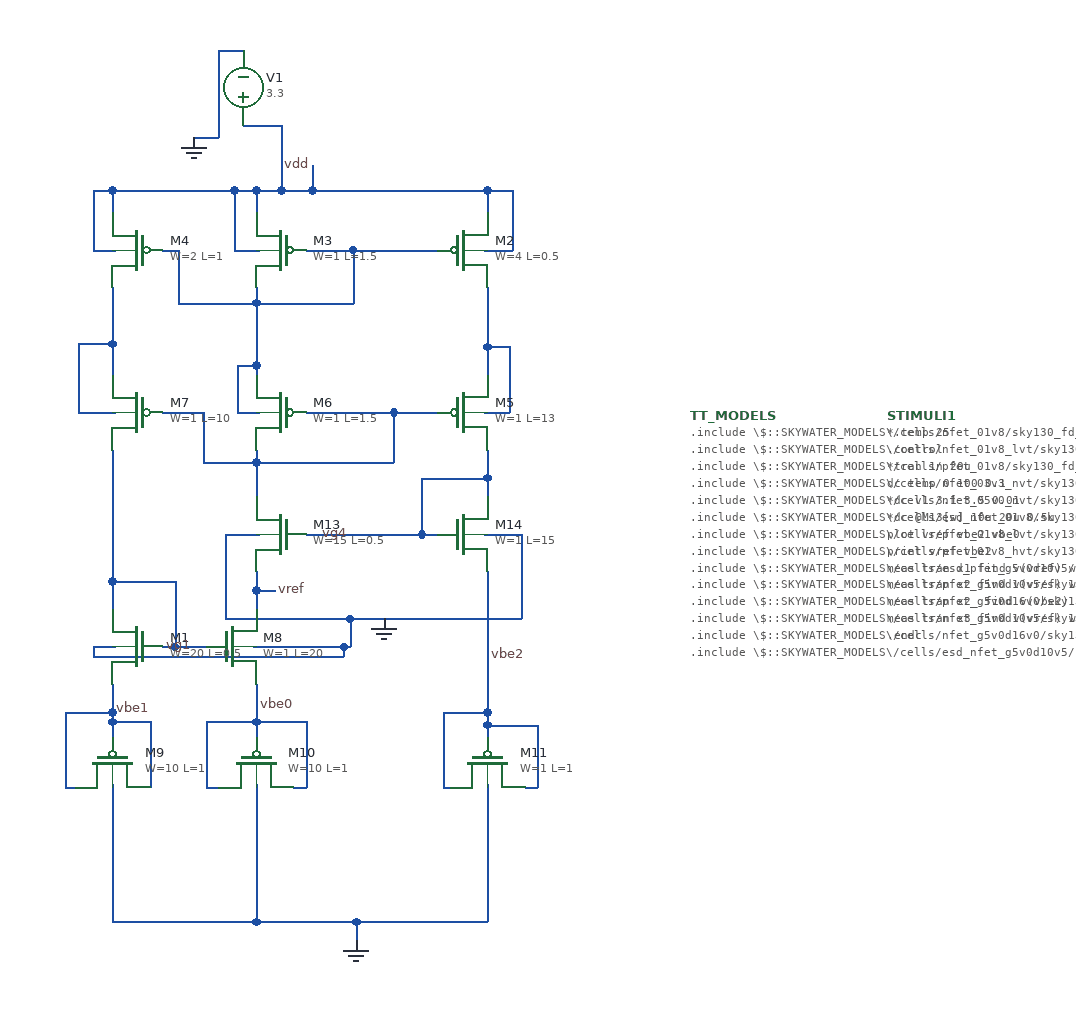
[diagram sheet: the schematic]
v {xschem version=2.9.9 file_version=1.2 }
G {}
K {}
V {}
S {}
E {}
N -125 -927.5 -125 -910 { lab=vdd}
N -27.5 -927.5 -10 -927.5 { lab=vdd}
N -10 -927.5 -10 -910 { lab=vdd}
N 175 -927.5 175 -910 { lab=vdd}
N 35 -927.5 175 -927.5 { lab=vdd}
N -27.5 -880 -7.5 -880 { lab=vdd}
N -27.5 -927.5 -27.5 -880 { lab=vdd}
N -140 -880 -122.5 -880 { lab=vdd}
N -140 -927.5 -140 -880 { lab=vdd}
N -140 -927.5 -125 -927.5 { lab=vdd}
N -125 -805 -125 -780 { lab=#net1}
N -152.5 -750 -122.5 -750 { lab=#net1}
N -152.5 -805 -152.5 -750 { lab=#net1}
N -152.5 -805 -125 -805 { lab=#net1}
N -125 -615 -125 -592.5 { lab=vg1}
N -85 -750 -52.5 -750 { lab=#net2}
N -52.5 -750 -52.5 -710 { lab=#net2}
N 100 -750 100 -710 { lab=#net2}
N 30 -750 100 -750 { lab=#net2}
N 100 -750 135 -750 { lab=#net2}
N -25 -750 -7.5 -750 { lab=#net3}
N -25 -787.5 -25 -750 { lab=#net3}
N -25 -787.5 -10 -787.5 { lab=#net3}
N -10 -787.5 -10 -780 { lab=#net3}
N -10 -837.5 -10 -787.5 { lab=#net3}
N -85 -880 -72.5 -880 { lab=#net3}
N -72.5 -880 -72.5 -837.5 { lab=#net3}
N 67.5 -880 67.5 -837.5 { lab=#net3}
N 30 -880 67.5 -880 { lab=#net3}
N 67.5 -880 135 -880 { lab=#net3}
N 172.5 -880 195 -880 { lab=vdd}
N 195 -927.5 195 -880 { lab=vdd}
N 175 -927.5 195 -927.5 { lab=vdd}
N 175 -802.5 175 -780 { lab=#net4}
N 172.5 -750 192.5 -750 { lab=#net4}
N 192.5 -802.5 192.5 -750 { lab=#net4}
N 175 -802.5 192.5 -802.5 { lab=#net4}
N 175 -697.5 175 -682.5 { lab=vg4}
N -10 -710 -10 -682.5 { lab=#net2}
N 122.5 -652.5 135 -652.5 { lab=vg4}
N 122.5 -697.5 175 -697.5 { lab=vg4}
N 122.5 -697.5 122.5 -652.5 { lab=vg4}
N -10 -607.5 -10 -592.5 { lab=vref}
N -75 -562.5 -50 -562.5 { lab=vg1}
N -95 -502.5 -95 -450 { lab=vbe1}
N -162.5 -450 -155 -450 { lab=vbe1}
N -50 -450 -40 -450 { lab=vbe0}
N -50 -502.5 -50 -450 { lab=vbe0}
N 20 -450 30 -450 { lab=vbe0}
N 30 -502.5 30 -450 { lab=vbe0}
N 140 -450 145 -450 { lab=vbe2}
N 205 -450 215 -450 { lab=vbe2}
N 215 -500 215 -450 { lab=vbe2}
N -125 -615 -75 -615 { lab=vg1}
N -75 -615 -75 -562.5 { lab=vg1}
N 175 -452.5 175 -342.5 { lab=GND}
N -125 -452.5 -125 -342.5 { lab=GND}
N -10 -452.5 -10 -342.5 { lab=GND}
N -60 -970 -40 -970 { lab=GND}
N 35 -947.5 35 -927.5 { lab=vdd}
N 70 -342.5 70 -327.5 { lab=GND}
N -10 -607.5 5 -607.5 { lab=vref}
N -35 -652.5 -7.5 -652.5 { lab=GND}
N -35 -652.5 -35 -585 { lab=GND}
N 65 -585 202.5 -585 { lab=GND}
N 172.5 -652.5 202.5 -652.5 { lab=GND}
N 202.5 -652.5 202.5 -585 { lab=GND}
N 65 -585 65 -562.5 { lab=GND}
N -140 -562.5 -122.5 -562.5 { lab=GND}
N -140 -562.5 -140 -555 { lab=GND}
N -52.5 -710 -10 -710 { lab=#net2}
N -10 -710 100 -710 { lab=#net2}
N -10 -532.5 -10 -502.5 { lab=vbe0}
N -10 -837.5 67.5 -837.5 { lab=#net3}
N -72.5 -837.5 -10 -837.5 { lab=#net3}
N 70 -342.5 175 -342.5 { lab=GND}
N -10 -342.5 70 -342.5 { lab=GND}
N -20 -980 10 -980 { lab=vdd}
N 10 -980 10 -927.5 { lab=vdd}
N -40 -1040 -20 -1040 { lab=GND}
N -40 -1040 -40 -970 { lab=GND}
N -125 -502.5 -125 -490 { lab=vbe1}
N -125 -532.5 -125 -510 { lab=vbe1}
N -125 -502.5 -95 -502.5 { lab=vbe1}
N -162.5 -510 -162.5 -450 { lab=vbe1}
N -162.5 -510 -125 -510 { lab=vbe1}
N 175 -500 215 -500 { lab=vbe2}
N 175 -500 175 -490 { lab=vbe2}
N 175 -510 175 -500 { lab=vbe2}
N 140 -510 140 -450 { lab=vbe2}
N 140 -510 175 -510 { lab=vbe2}
N -10 -502.5 -10 -490 { lab=vbe0}
N -50 -502.5 -10 -502.5 { lab=vbe0}
N 60 -562.5 65 -562.5 { lab=GND}
N -140 -555 60 -555 { lab=GND}
N 60 -562.5 60 -555 { lab=GND}
N -10 -502.5 30 -502.5 { lab=vbe0}
N -125 -927.5 -27.5 -927.5 { lab=vdd}
N -125 -850 -125 -805 { lab=#net1}
N 175 -850 175 -802.5 { lab=#net4}
N 175 -720 175 -697.5 { lab=vg4}
N 30 -652.5 122.5 -652.5 { lab=vg4}
N -125 -720 -125 -615 { lab=vg1}
N -85 -562.5 -75 -562.5 { lab=vg1}
N -10 -927.5 10 -927.5 { lab=vdd}
N 10 -927.5 35 -927.5 { lab=vdd}
N -10 -622.5 -10 -607.5 { lab=vref}
N -35 -585 65 -585 { lab=GND}
N -10 -720 -10 -710 { lab=#net2}
N -10 -850 -10 -837.5 { lab=#net3}
N -125 -342.5 -10 -342.5 { lab=GND}
N -125 -510 -125 -502.5 { lab=vbe1}
N 175 -622.5 175 -510 { lab=vbe2}
N -12.5 -562.5 60 -562.5 { lab=GND}
C {sky130_fd_pr/pfet_g5v0d10v5.sym} 155 -880 0 0 {name=M2
L=0.5
W=4
nf=1
mult=1
ad="'int((nf+1)/2) * W/nf * 0.29'" 
pd="'2*int((nf+1)/2) * (W/nf + 0.29)'"
as="'int((nf+2)/2) * W/nf * 0.29'" 
ps="'2*int((nf+2)/2) * (W/nf + 0.29)'"
nrd="'0.29 / W'" nrs="'0.29 / W'"
sa=0 sb=0 sd=0
model=pfet_g5v0d10v5
spiceprefix=X
}
C {sky130_fd_pr/pfet_g5v0d10v5.sym} 10 -880 0 1 {name=M3
L=1.5
W=1
nf=1
mult=1
ad="'int((nf+1)/2) * W/nf * 0.29'" 
pd="'2*int((nf+1)/2) * (W/nf + 0.29)'"
as="'int((nf+2)/2) * W/nf * 0.29'" 
ps="'2*int((nf+2)/2) * (W/nf + 0.29)'"
nrd="'0.29 / W'" nrs="'0.29 / W'"
sa=0 sb=0 sd=0
model=pfet_g5v0d10v5
spiceprefix=X
}
C {sky130_fd_pr/pfet_g5v0d10v5.sym} -105 -880 0 1 {name=M4
L=1
W=2
nf=1
mult=1
ad="'int((nf+1)/2) * W/nf * 0.29'" 
pd="'2*int((nf+1)/2) * (W/nf + 0.29)'"
as="'int((nf+2)/2) * W/nf * 0.29'" 
ps="'2*int((nf+2)/2) * (W/nf + 0.29)'"
nrd="'0.29 / W'" nrs="'0.29 / W'"
sa=0 sb=0 sd=0
model=pfet_g5v0d10v5
spiceprefix=X
}
C {sky130_fd_pr/pfet_g5v0d10v5.sym} 155 -750 0 0 {name=M5
L=13
W=1
nf=1
mult=1
ad="'int((nf+1)/2) * W/nf * 0.29'" 
pd="'2*int((nf+1)/2) * (W/nf + 0.29)'"
as="'int((nf+2)/2) * W/nf * 0.29'" 
ps="'2*int((nf+2)/2) * (W/nf + 0.29)'"
nrd="'0.29 / W'" nrs="'0.29 / W'"
sa=0 sb=0 sd=0
model=pfet_g5v0d10v5
spiceprefix=X
}
C {sky130_fd_pr/pfet_g5v0d10v5.sym} 10 -750 0 1 {name=M6
L=1.5
W=1
nf=1
mult=1
ad="'int((nf+1)/2) * W/nf * 0.29'" 
pd="'2*int((nf+1)/2) * (W/nf + 0.29)'"
as="'int((nf+2)/2) * W/nf * 0.29'" 
ps="'2*int((nf+2)/2) * (W/nf + 0.29)'"
nrd="'0.29 / W'" nrs="'0.29 / W'"
sa=0 sb=0 sd=0
model=pfet_g5v0d10v5
spiceprefix=X
}
C {sky130_fd_pr/pfet_g5v0d10v5.sym} -105 -750 0 1 {name=M7
L=10
W=1
nf=1
mult=1
ad="'int((nf+1)/2) * W/nf * 0.29'" 
pd="'2*int((nf+1)/2) * (W/nf + 0.29)'"
as="'int((nf+2)/2) * W/nf * 0.29'" 
ps="'2*int((nf+2)/2) * (W/nf + 0.29)'"
nrd="'0.29 / W'" nrs="'0.29 / W'"
sa=0 sb=0 sd=0
model=pfet_g5v0d10v5
spiceprefix=X
}
C {sky130_fd_pr/pfet_g5v0d10v5.sym} -125 -470 3 1 {name=M9
L=1
W=10
nf=1
mult=1
ad="'int((nf+1)/2) * W/nf * 0.29'" 
pd="'2*int((nf+1)/2) * (W/nf + 0.29)'"
as="'int((nf+2)/2) * W/nf * 0.29'" 
ps="'2*int((nf+2)/2) * (W/nf + 0.29)'"
nrd="'0.29 / W'" nrs="'0.29 / W'"
sa=0 sb=0 sd=0
model=pfet_g5v0d10v5
spiceprefix=X
}
C {sky130_fd_pr/pfet_g5v0d10v5.sym} -10 -470 3 1 {name=M10
L=1
W=10
nf=1
mult=1
ad="'int((nf+1)/2) * W/nf * 0.29'" 
pd="'2*int((nf+1)/2) * (W/nf + 0.29)'"
as="'int((nf+2)/2) * W/nf * 0.29'" 
ps="'2*int((nf+2)/2) * (W/nf + 0.29)'"
nrd="'0.29 / W'" nrs="'0.29 / W'"
sa=0 sb=0 sd=0
model=pfet_g5v0d10v5
spiceprefix=X
}
C {sky130_fd_pr/pfet_g5v0d10v5.sym} 175 -470 3 1 {name=M11
L=1
W=1
nf=1
mult=1
ad="'int((nf+1)/2) * W/nf * 0.29'" 
pd="'2*int((nf+1)/2) * (W/nf + 0.29)'"
as="'int((nf+2)/2) * W/nf * 0.29'" 
ps="'2*int((nf+2)/2) * (W/nf + 0.29)'"
nrd="'0.29 / W'" nrs="'0.29 / W'"
sa=0 sb=0 sd=0
model=pfet_g5v0d10v5
spiceprefix=X
}
C {devices/gnd.sym} 70 -327.5 0 0 {name=l1 lab=GND}
C {devices/vsource.sym} -20 -1010 2 0 {name=V1 value="3.3"
*name=V1 value="pwl 0 0 2u 0 2u 3.1 4u 3.1 4u 3.15 6u 3.15 6u 3.2 8u 3.2 8u 3.25 10u 3.25 10u 3.3 12u 3.3 12u 3.35 14u 3.35 14u 3.4 16u 3.4 16u 3.45 18u 3.45 18u 3.5"
*name=V1 value="pwl 0 0 2u 0 2u 1.4 4u 1.4 4u 1.45 6u 1.45 6u 1.5 8u 1.5 8u 1.55 10u 1.55 10u 1.6 12u 1.6 12u 1.65 14u 1.65 14u 1.7 16u 1.7 16u 1.75 18u 1.75 18u 1.8"
}
C {devices/gnd.sym} -60 -970 0 0 {name=l2 lab=GND}
C {devices/code.sym} 337.5 -747.5 0 0 {name=TT_MODELS
only_toplevel=true
format="tcleval( @value )"
value="
.include \\\\$::SKYWATER_MODELS\\\\/cells/nfet_01v8/sky130_fd_pr__nfet_01v8__tt.corner.spice
.include \\\\$::SKYWATER_MODELS\\\\/cells/nfet_01v8_lvt/sky130_fd_pr__nfet_01v8_lvt__tt.corner.spice
.include \\\\$::SKYWATER_MODELS\\\\/cells/pfet_01v8/sky130_fd_pr__pfet_01v8__tt.corner.spice
.include \\\\$::SKYWATER_MODELS\\\\/cells/nfet_03v3_nvt/sky130_fd_pr__nfet_03v3_nvt__tt.corner.spice
.include \\\\$::SKYWATER_MODELS\\\\/cells/nfet_05v0_nvt/sky130_fd_pr__nfet_05v0_nvt__tt.corner.spice
.include \\\\$::SKYWATER_MODELS\\\\/cells/esd_nfet_01v8/sky130_fd_pr__esd_nfet_01v8__tt.corner.spice
.include \\\\$::SKYWATER_MODELS\\\\/cells/pfet_01v8_lvt/sky130_fd_pr__pfet_01v8_lvt__tt.corner.spice
.include \\\\$::SKYWATER_MODELS\\\\/cells/pfet_01v8_hvt/sky130_fd_pr__pfet_01v8_hvt__tt.corner.spice
.include \\\\$::SKYWATER_MODELS\\\\/cells/esd_pfet_g5v0d10v5/sky130_fd_pr__esd_pfet_g5v0d10v5__tt.corner.spice
.include \\\\$::SKYWATER_MODELS\\\\/cells/pfet_g5v0d10v5/sky130_fd_pr__pfet_g5v0d10v5__tt.corner.spice
.include \\\\$::SKYWATER_MODELS\\\\/cells/pfet_g5v0d16v0/sky130_fd_pr__pfet_g5v0d16v0__tt.corner.spice
.include \\\\$::SKYWATER_MODELS\\\\/cells/nfet_g5v0d10v5/sky130_fd_pr__nfet_g5v0d10v5__tt.corner.spice
.include \\\\$::SKYWATER_MODELS\\\\/cells/nfet_g5v0d16v0/sky130_fd_pr__nfet_g5v0d16v0__tt_discrete.corner.spice
.include \\\\$::SKYWATER_MODELS\\\\/cells/esd_nfet_g5v0d10v5/sky130_fd_pr__esd_nfet_g5v0d10v5__tt.corner.spice
.include \\\\$::SKYWATER_MODELS\\\\/models/corners/tt/nonfet.spice
* Mismatch parameters
.include \\\\$::SKYWATER_MODELS\\\\/cells/nfet_01v8/sky130_fd_pr__nfet_01v8__mismatch.corner.spice
.include \\\\$::SKYWATER_MODELS\\\\/cells/pfet_01v8/sky130_fd_pr__pfet_01v8__mismatch.corner.spice
.include \\\\$::SKYWATER_MODELS\\\\/cells/nfet_01v8_lvt/sky130_fd_pr__nfet_01v8_lvt__mismatch.corner.spice
.include \\\\$::SKYWATER_MODELS\\\\/cells/pfet_01v8_lvt/sky130_fd_pr__pfet_01v8_lvt__mismatch.corner.spice
.include \\\\$::SKYWATER_MODELS\\\\/cells/pfet_01v8_hvt/sky130_fd_pr__pfet_01v8_hvt__mismatch.corner.spice
.include \\\\$::SKYWATER_MODELS\\\\/cells/nfet_g5v0d10v5/sky130_fd_pr__nfet_g5v0d10v5__mismatch.corner.spice
.include \\\\$::SKYWATER_MODELS\\\\/cells/pfet_g5v0d10v5/sky130_fd_pr__pfet_g5v0d10v5__mismatch.corner.spice
.include \\\\$::SKYWATER_MODELS\\\\/cells/nfet_05v0_nvt/sky130_fd_pr__nfet_05v0_nvt__mismatch.corner.spice
.include \\\\$::SKYWATER_MODELS\\\\/cells/nfet_03v3_nvt/sky130_fd_pr__nfet_03v3_nvt__mismatch.corner.spice
* Resistor\\\\$::SKYWATER_MODELS\\\\/Capacitor
.include \\\\$::SKYWATER_MODELS\\\\/models/r+c/res_typical__cap_typical.spice
.include \\\\$::SKYWATER_MODELS\\\\/models/r+c/res_typical__cap_typical__lin.spice
* Special cells
.include \\\\$::SKYWATER_MODELS\\\\/models/corners/tt/specialized_cells.spice
* All models
.include \\\\$::SKYWATER_MODELS\\\\/models/all.spice
* Corner
.include \\\\$::SKYWATER_MODELS\\\\/models/corners/tt/rf.spice
"}
C {devices/code.sym} 495 -747.5 0 0 {name=STIMULI1 
only_toplevel=true
place=end
value="
*.temp 25
.control
*tran 1n 20u
dc temp 0 100 0.1
*dc v1 3.1 3.5 0.01
*dc @M13[w] 10u 20u 0.5u
plot vref vbe2 vbe0
print vref vbe2
meas tran x1 find v(vref) when v(vdd)=3.2
meas tran x2 find v(vref) when v(vdd)=3.3
meas tran x2_ find v(vbe2) when v(vdd)=3.3
meas tran x3 find v(vref) when v(vdd)=3.4
.endc
"}
C {devices/lab_pin.sym} 35 -947.5 1 0 {name=l5 sig_type=std_logic lab=vdd}
C {devices/lab_pin.sym} 5 -607.5 2 0 {name=l3 sig_type=std_logic lab=vref}
C {devices/gnd.sym} 92.5 -585 0 0 {name=l4 lab=GND}
C {sky130_fd_pr/nfet_g5v0d10v5.sym} 155 -652.5 0 0 {name=M14
L=15
W=1
nf=1
mult=1
ad="'int((nf+1)/2) * W/nf * 0.29'" 
pd="'2*int((nf+1)/2) * (W/nf + 0.29)'"
as="'int((nf+2)/2) * W/nf * 0.29'" 
ps="'2*int((nf+2)/2) * (W/nf + 0.29)'"
nrd="'0.29 / W'" nrs="'0.29 / W'"
sa=0 sb=0 sd=0
model=nfet_g5v0d10v5
spiceprefix=X
}
C {sky130_fd_pr/nfet_g5v0d10v5.sym} -30 -562.5 0 0 {name=M8
L=20
W=1
nf=1
mult=1
ad="'int((nf+1)/2) * W/nf * 0.29'" 
pd="'2*int((nf+1)/2) * (W/nf + 0.29)'"
as="'int((nf+2)/2) * W/nf * 0.29'" 
ps="'2*int((nf+2)/2) * (W/nf + 0.29)'"
nrd="'0.29 / W'" nrs="'0.29 / W'"
sa=0 sb=0 sd=0
model=nfet_g5v0d10v5
spiceprefix=X
}
C {sky130_fd_pr/nfet_g5v0d10v5.sym} 10 -652.5 0 1 {name=M13
L=0.5
W=15
nf=1
mult=1
ad="'int((nf+1)/2) * W/nf * 0.29'" 
pd="'2*int((nf+1)/2) * (W/nf + 0.29)'"
as="'int((nf+2)/2) * W/nf * 0.29'" 
ps="'2*int((nf+2)/2) * (W/nf + 0.29)'"
nrd="'0.29 / W'" nrs="'0.29 / W'"
sa=0 sb=0 sd=0
model=nfet_g5v0d10v5
spiceprefix=X
}
C {sky130_fd_pr/nfet_g5v0d10v5.sym} -105 -562.5 0 1 {name=M1
L=0.5
W=20
nf=1
mult=1
ad="'int((nf+1)/2) * W/nf * 0.29'" 
pd="'2*int((nf+1)/2) * (W/nf + 0.29)'"
as="'int((nf+2)/2) * W/nf * 0.29'" 
ps="'2*int((nf+2)/2) * (W/nf + 0.29)'"
nrd="'0.29 / W'" nrs="'0.29 / W'"
sa=0 sb=0 sd=0
model=nfet_g5v0d10v5
spiceprefix=X
}
C {devices/lab_pin.sym} 175 -555 2 0 {name=l6 sig_type=std_logic lab=vbe2}
C {devices/lab_pin.sym} -10 -515 2 0 {name=l7 sig_type=std_logic lab=vbe0}
C {devices/lab_pin.sym} 65 -652.5 3 0 {name=l8 sig_type=std_logic lab=vg4}
C {devices/lab_pin.sym} -60 -562.5 3 0 {name=l9 sig_type=std_logic lab=vg1}
C {devices/lab_pin.sym} -125 -512.5 2 0 {name=l10 sig_type=std_logic lab=vbe1}
